VERSION 5.7 ;
  NOWIREEXTENSIONATPIN ON ;
  DIVIDERCHAR "/" ;
  BUSBITCHARS "[]" ;
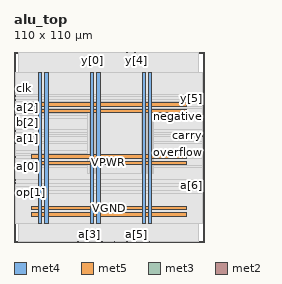
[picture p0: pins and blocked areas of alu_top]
MACRO alu_top
  CLASS BLOCK ;
  FOREIGN alu_top ;
  ORIGIN 0.000 0.000 ;
  SIZE 110.000 BY 110.000 ;
  PIN VGND
    DIRECTION INOUT ;
    USE GROUND ;
    PORT
      LAYER met4 ;
        RECT 17.820 10.640 19.820 98.160 ;
    END
    PORT
      LAYER met4 ;
        RECT 47.820 10.640 49.820 98.160 ;
    END
    PORT
      LAYER met4 ;
        RECT 77.820 10.640 79.820 98.160 ;
    END
    PORT
      LAYER met5 ;
        RECT 10.120 18.580 99.820 20.580 ;
    END
    PORT
      LAYER met5 ;
        RECT 10.120 48.580 99.820 50.580 ;
    END
    PORT
      LAYER met5 ;
        RECT 10.120 78.580 99.820 80.580 ;
    END
  END VGND
  PIN VPWR
    DIRECTION INOUT ;
    USE POWER ;
    PORT
      LAYER met4 ;
        RECT 14.120 10.640 16.120 98.160 ;
    END
    PORT
      LAYER met4 ;
        RECT 44.120 10.640 46.120 98.160 ;
    END
    PORT
      LAYER met4 ;
        RECT 74.120 10.640 76.120 98.160 ;
    END
    PORT
      LAYER met5 ;
        RECT 10.120 14.880 99.820 16.880 ;
    END
    PORT
      LAYER met5 ;
        RECT 10.120 44.880 99.820 46.880 ;
    END
    PORT
      LAYER met5 ;
        RECT 10.120 74.880 99.820 76.880 ;
    END
  END VPWR
  PIN a[0]
    DIRECTION INPUT ;
    USE SIGNAL ;
    ANTENNAGATEAREA 0.213000 ;
    PORT
      LAYER met3 ;
        RECT 0.000 43.560 0.600 44.160 ;
    END
  END a[0]
  PIN a[1]
    DIRECTION INPUT ;
    USE SIGNAL ;
    ANTENNAGATEAREA 0.213000 ;
    PORT
      LAYER met3 ;
        RECT 0.000 63.960 0.600 64.560 ;
    END
  END a[1]
  PIN a[2]
    DIRECTION INPUT ;
    USE SIGNAL ;
    ANTENNAGATEAREA 0.213000 ;
    PORT
      LAYER met3 ;
        RECT 0.000 77.560 0.600 78.160 ;
    END
  END a[2]
  PIN a[3]
    DIRECTION INPUT ;
    USE SIGNAL ;
    ANTENNAGATEAREA 0.213000 ;
    PORT
      LAYER met2 ;
        RECT 43.330 0.000 43.610 0.280 ;
    END
  END a[3]
  PIN a[4]
    DIRECTION INPUT ;
    USE SIGNAL ;
    ANTENNAGATEAREA 0.213000 ;
    PORT
      LAYER met2 ;
        RECT 58.050 0.000 58.330 0.280 ;
    END
  END a[4]
  PIN a[5]
    DIRECTION INPUT ;
    USE SIGNAL ;
    ANTENNAGATEAREA 0.213000 ;
    PORT
      LAYER met2 ;
        RECT 70.930 0.000 71.210 0.280 ;
    END
  END a[5]
  PIN a[6]
    DIRECTION INPUT ;
    USE SIGNAL ;
    ANTENNAGATEAREA 0.213000 ;
    PORT
      LAYER met3 ;
        RECT 109.400 32.680 110.000 33.280 ;
    END
  END a[6]
  PIN a[7]
    DIRECTION INPUT ;
    USE SIGNAL ;
    ANTENNAGATEAREA 0.213000 ;
    PORT
      LAYER met2 ;
        RECT 70.010 109.720 70.290 110.000 ;
    END
  END a[7]
  PIN b[0]
    DIRECTION INPUT ;
    USE SIGNAL ;
    ANTENNAGATEAREA 0.213000 ;
    PORT
      LAYER met3 ;
        RECT 0.000 57.160 0.600 57.760 ;
    END
  END b[0]
  PIN b[1]
    DIRECTION INPUT ;
    USE SIGNAL ;
    ANTENNAGATEAREA 0.213000 ;
    PORT
      LAYER met3 ;
        RECT 0.000 49.000 0.600 49.600 ;
    END
  END b[1]
  PIN b[2]
    DIRECTION INPUT ;
    USE SIGNAL ;
    ANTENNAGATEAREA 0.213000 ;
    PORT
      LAYER met3 ;
        RECT 0.000 73.480 0.600 74.080 ;
    END
  END b[2]
  PIN b[3]
    DIRECTION INPUT ;
    USE SIGNAL ;
    ANTENNAGATEAREA 0.213000 ;
    PORT
      LAYER met2 ;
        RECT 36.890 0.000 37.170 0.280 ;
    END
  END b[3]
  PIN b[4]
    DIRECTION INPUT ;
    USE SIGNAL ;
    ANTENNAGATEAREA 0.213000 ;
    PORT
      LAYER met2 ;
        RECT 50.690 0.000 50.970 0.280 ;
    END
  END b[4]
  PIN b[5]
    DIRECTION INPUT ;
    USE SIGNAL ;
    ANTENNAGATEAREA 0.213000 ;
    PORT
      LAYER met2 ;
        RECT 65.410 0.000 65.690 0.280 ;
    END
  END b[5]
  PIN b[6]
    DIRECTION INPUT ;
    USE SIGNAL ;
    ANTENNAGATEAREA 0.213000 ;
    PORT
      LAYER met2 ;
        RECT 78.290 0.000 78.570 0.280 ;
    END
  END b[6]
  PIN b[7]
    DIRECTION INPUT ;
    USE SIGNAL ;
    ANTENNAGATEAREA 0.213000 ;
    PORT
      LAYER met2 ;
        RECT 65.410 109.720 65.690 110.000 ;
    END
  END b[7]
  PIN carry
    DIRECTION OUTPUT ;
    USE SIGNAL ;
    ANTENNAGATEAREA 0.126000 ;
    ANTENNADIFFAREA 0.429000 ;
    PORT
      LAYER met3 ;
        RECT 109.400 61.240 110.000 61.840 ;
    END
  END carry
  PIN clk
    DIRECTION INPUT ;
    USE SIGNAL ;
    ANTENNAGATEAREA 0.852000 ;
    PORT
      LAYER met3 ;
        RECT 0.000 84.360 0.600 84.960 ;
    END
  END clk
  PIN negative
    DIRECTION OUTPUT ;
    USE SIGNAL ;
    ANTENNAGATEAREA 0.126000 ;
    ANTENNADIFFAREA 0.429000 ;
    PORT
      LAYER met3 ;
        RECT 109.400 72.120 110.000 72.720 ;
    END
  END negative
  PIN op[0]
    DIRECTION INPUT ;
    USE SIGNAL ;
    ANTENNAGATEAREA 0.213000 ;
    PORT
      LAYER met3 ;
        RECT 0.000 35.400 0.600 36.000 ;
    END
  END op[0]
  PIN op[1]
    DIRECTION INPUT ;
    USE SIGNAL ;
    ANTENNAGATEAREA 0.213000 ;
    PORT
      LAYER met3 ;
        RECT 0.000 28.600 0.600 29.200 ;
    END
  END op[1]
  PIN op[2]
    DIRECTION INPUT ;
    USE SIGNAL ;
    ANTENNAGATEAREA 0.213000 ;
    PORT
      LAYER met3 ;
        RECT 0.000 34.040 0.600 34.640 ;
    END
  END op[2]
  PIN overflow
    DIRECTION OUTPUT ;
    USE SIGNAL ;
    ANTENNAGATEAREA 0.126000 ;
    ANTENNADIFFAREA 0.429000 ;
    PORT
      LAYER met3 ;
        RECT 109.400 51.720 110.000 52.320 ;
    END
  END overflow
  PIN rst_n
    DIRECTION INPUT ;
    USE SIGNAL ;
    ANTENNAGATEAREA 0.213000 ;
    PORT
      LAYER met3 ;
        RECT 0.000 81.640 0.600 82.240 ;
    END
  END rst_n
  PIN y[0]
    DIRECTION OUTPUT ;
    USE SIGNAL ;
    ANTENNAGATEAREA 0.126000 ;
    ANTENNADIFFAREA 0.429000 ;
    PORT
      LAYER met2 ;
        RECT 45.170 109.720 45.450 110.000 ;
    END
  END y[0]
  PIN y[1]
    DIRECTION OUTPUT ;
    USE SIGNAL ;
    ANTENNAGATEAREA 0.126000 ;
    ANTENNADIFFAREA 0.429000 ;
    PORT
      LAYER met2 ;
        RECT 35.970 109.720 36.250 110.000 ;
    END
  END y[1]
  PIN y[2]
    DIRECTION OUTPUT ;
    USE SIGNAL ;
    ANTENNAGATEAREA 0.126000 ;
    ANTENNADIFFAREA 0.429000 ;
    PORT
      LAYER met2 ;
        RECT 56.210 109.720 56.490 110.000 ;
    END
  END y[2]
  PIN y[3]
    DIRECTION OUTPUT ;
    USE SIGNAL ;
    ANTENNAGATEAREA 0.126000 ;
    ANTENNADIFFAREA 0.429000 ;
    PORT
      LAYER met2 ;
        RECT 64.490 109.720 64.770 110.000 ;
    END
  END y[3]
  PIN y[4]
    DIRECTION OUTPUT ;
    USE SIGNAL ;
    ANTENNAGATEAREA 0.126000 ;
    ANTENNADIFFAREA 0.429000 ;
    PORT
      LAYER met2 ;
        RECT 70.930 109.720 71.210 110.000 ;
    END
  END y[4]
  PIN y[5]
    DIRECTION OUTPUT ;
    USE SIGNAL ;
    ANTENNAGATEAREA 0.126000 ;
    ANTENNADIFFAREA 0.429000 ;
    PORT
      LAYER met3 ;
        RECT 109.400 83.000 110.000 83.600 ;
    END
  END y[5]
  PIN y[6]
    DIRECTION OUTPUT ;
    USE SIGNAL ;
    ANTENNAGATEAREA 0.126000 ;
    ANTENNADIFFAREA 0.429000 ;
    PORT
      LAYER met3 ;
        RECT 109.400 81.640 110.000 82.240 ;
    END
  END y[6]
  PIN y[7]
    DIRECTION OUTPUT ;
    USE SIGNAL ;
    ANTENNAGATEAREA 0.126000 ;
    ANTENNADIFFAREA 0.429000 ;
    PORT
      LAYER met3 ;
        RECT 109.400 73.480 110.000 74.080 ;
    END
  END y[7]
  PIN zero
    DIRECTION OUTPUT ;
    USE SIGNAL ;
    ANTENNAGATEAREA 0.126000 ;
    ANTENNADIFFAREA 0.429000 ;
    PORT
      LAYER met3 ;
        RECT 109.400 78.920 110.000 79.520 ;
    END
  END zero
  OBS
      LAYER nwell ;
        RECT 9.930 10.795 100.010 98.005 ;
      LAYER li1 ;
        RECT 10.120 10.795 99.820 98.005 ;
      LAYER met1 ;
        RECT 2.830 10.640 106.650 98.160 ;
      LAYER met2 ;
        RECT 2.850 109.440 35.690 109.720 ;
        RECT 36.530 109.440 44.890 109.720 ;
        RECT 45.730 109.440 55.930 109.720 ;
        RECT 56.770 109.440 64.210 109.720 ;
        RECT 65.050 109.440 65.130 109.720 ;
        RECT 65.970 109.440 69.730 109.720 ;
        RECT 70.570 109.440 70.650 109.720 ;
        RECT 71.490 109.440 106.630 109.720 ;
        RECT 2.850 0.560 106.630 109.440 ;
        RECT 2.850 0.070 36.610 0.560 ;
        RECT 37.450 0.070 43.050 0.560 ;
        RECT 43.890 0.070 50.410 0.560 ;
        RECT 51.250 0.070 57.770 0.560 ;
        RECT 58.610 0.070 65.130 0.560 ;
        RECT 65.970 0.070 70.650 0.560 ;
        RECT 71.490 0.070 78.010 0.560 ;
        RECT 78.850 0.070 106.630 0.560 ;
      LAYER met3 ;
        RECT 0.600 85.360 109.400 98.085 ;
        RECT 1.000 84.000 109.400 85.360 ;
        RECT 1.000 83.960 109.000 84.000 ;
        RECT 0.600 82.640 109.000 83.960 ;
        RECT 1.000 81.240 109.000 82.640 ;
        RECT 0.600 79.920 109.400 81.240 ;
        RECT 0.600 78.560 109.000 79.920 ;
        RECT 1.000 78.520 109.000 78.560 ;
        RECT 1.000 77.160 109.400 78.520 ;
        RECT 0.600 74.480 109.400 77.160 ;
        RECT 1.000 73.080 109.000 74.480 ;
        RECT 0.600 71.720 109.000 73.080 ;
        RECT 0.600 64.960 109.400 71.720 ;
        RECT 1.000 63.560 109.400 64.960 ;
        RECT 0.600 62.240 109.400 63.560 ;
        RECT 0.600 60.840 109.000 62.240 ;
        RECT 0.600 58.160 109.400 60.840 ;
        RECT 1.000 56.760 109.400 58.160 ;
        RECT 0.600 52.720 109.400 56.760 ;
        RECT 0.600 51.320 109.000 52.720 ;
        RECT 0.600 50.000 109.400 51.320 ;
        RECT 1.000 48.600 109.400 50.000 ;
        RECT 0.600 44.560 109.400 48.600 ;
        RECT 1.000 43.160 109.400 44.560 ;
        RECT 0.600 36.400 109.400 43.160 ;
        RECT 1.000 33.680 109.400 36.400 ;
        RECT 1.000 33.640 109.000 33.680 ;
        RECT 0.600 32.280 109.000 33.640 ;
        RECT 0.600 29.600 109.400 32.280 ;
        RECT 1.000 28.200 109.400 29.600 ;
        RECT 0.600 10.715 109.400 28.200 ;
      LAYER met4 ;
        RECT 42.615 39.615 43.720 75.305 ;
        RECT 46.520 39.615 47.420 75.305 ;
        RECT 50.220 39.615 73.720 75.305 ;
        RECT 76.520 39.615 77.420 75.305 ;
        RECT 80.220 39.615 80.665 75.305 ;
  END
END alu_top
END LIBRARY

